VERSION 5.7 ;
  NAMESCASESENSITIVE ON ;
  NOWIREEXTENSIONATPIN ON ;
  DIVIDERCHAR "/" ;
  BUSBITCHARS "[]" ;
UNITS
  DATABASE MICRONS 200 ;
END UNITS

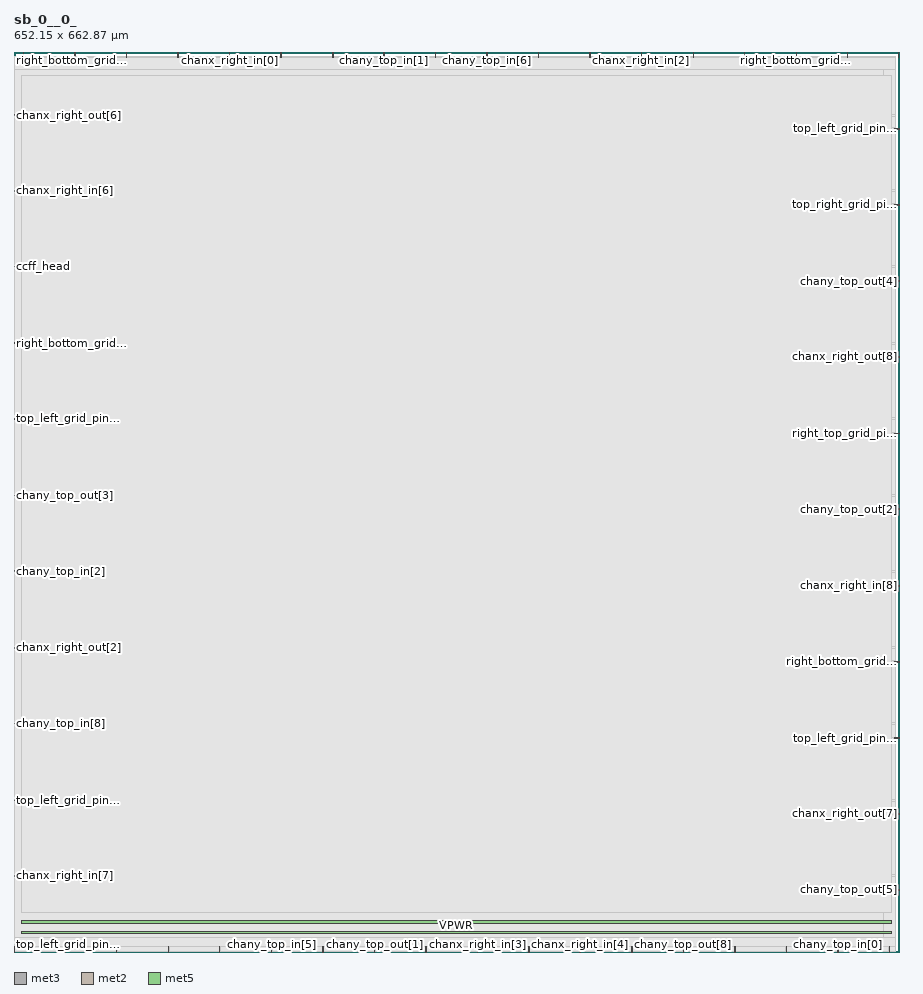
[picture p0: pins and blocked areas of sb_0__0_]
MACRO sb_0__0_
  CLASS BLOCK ;
  FOREIGN sb_0__0_ ;
  ORIGIN 0.000 0.000 ;
  SIZE 652.150 BY 662.870 ;
  PIN ccff_head
    DIRECTION INPUT ;
    PORT
      LAYER met3 ;
        RECT 0.000 504.600 4.000 505.200 ;
    END
  END ccff_head
  PIN ccff_tail
    DIRECTION OUTPUT TRISTATE ;
    PORT
      LAYER met2 ;
        RECT 234.690 658.870 234.970 662.870 ;
    END
  END ccff_tail
  PIN chanx_right_in[0]
    DIRECTION INPUT ;
    PORT
      LAYER met2 ;
        RECT 158.790 658.870 159.070 662.870 ;
    END
  END chanx_right_in[0]
  PIN chanx_right_in[1]
    DIRECTION INPUT ;
    PORT
      LAYER met2 ;
        RECT 44.710 658.870 44.990 662.870 ;
    END
  END chanx_right_in[1]
  PIN chanx_right_in[2]
    DIRECTION INPUT ;
    PORT
      LAYER met2 ;
        RECT 461.930 658.870 462.210 662.870 ;
    END
  END chanx_right_in[2]
  PIN chanx_right_in[3]
    DIRECTION INPUT ;
    PORT
      LAYER met2 ;
        RECT 341.410 0.000 341.690 4.000 ;
    END
  END chanx_right_in[3]
  PIN chanx_right_in[4]
    DIRECTION INPUT ;
    PORT
      LAYER met2 ;
        RECT 416.850 0.000 417.130 4.000 ;
    END
  END chanx_right_in[4]
  PIN chanx_right_in[5]
    DIRECTION INPUT ;
    PORT
      LAYER met2 ;
        RECT 386.030 658.870 386.310 662.870 ;
    END
  END chanx_right_in[5]
  PIN chanx_right_in[6]
    DIRECTION INPUT ;
    PORT
      LAYER met3 ;
        RECT 0.000 560.360 4.000 560.960 ;
    END
  END chanx_right_in[6]
  PIN chanx_right_in[7]
    DIRECTION INPUT ;
    PORT
      LAYER met3 ;
        RECT 0.000 55.800 4.000 56.400 ;
    END
  END chanx_right_in[7]
  PIN chanx_right_in[8]
    DIRECTION INPUT ;
    PORT
      LAYER met3 ;
        RECT 648.150 269.320 652.150 269.920 ;
    END
  END chanx_right_in[8]
  PIN chanx_right_out[0]
    DIRECTION OUTPUT TRISTATE ;
    PORT
      LAYER met2 ;
        RECT 120.610 658.870 120.890 662.870 ;
    END
  END chanx_right_out[0]
  PIN chanx_right_out[1]
    DIRECTION OUTPUT TRISTATE ;
    PORT
      LAYER met2 ;
        RECT 455.030 0.000 455.310 4.000 ;
    END
  END chanx_right_out[1]
  PIN chanx_right_out[2]
    DIRECTION OUTPUT TRISTATE ;
    PORT
      LAYER met3 ;
        RECT 0.000 223.760 4.000 224.360 ;
    END
  END chanx_right_out[2]
  PIN chanx_right_out[3]
    DIRECTION OUTPUT TRISTATE ;
    PORT
      LAYER met2 ;
        RECT 500.110 658.870 500.390 662.870 ;
    END
  END chanx_right_out[3]
  PIN chanx_right_out[4]
    DIRECTION OUTPUT TRISTATE ;
    PORT
      LAYER met2 ;
        RECT 75.530 0.000 75.810 4.000 ;
    END
  END chanx_right_out[4]
  PIN chanx_right_out[5]
    DIRECTION OUTPUT TRISTATE ;
    PORT
      LAYER met2 ;
        RECT 644.550 0.000 644.830 4.000 ;
    END
  END chanx_right_out[5]
  PIN chanx_right_out[6]
    DIRECTION OUTPUT TRISTATE ;
    PORT
      LAYER met3 ;
        RECT 0.000 616.120 4.000 616.720 ;
    END
  END chanx_right_out[6]
  PIN chanx_right_out[7]
    DIRECTION OUTPUT TRISTATE ;
    PORT
      LAYER met3 ;
        RECT 648.150 101.360 652.150 101.960 ;
    END
  END chanx_right_out[7]
  PIN chanx_right_out[8]
    DIRECTION OUTPUT TRISTATE ;
    PORT
      LAYER met3 ;
        RECT 648.150 437.960 652.150 438.560 ;
    END
  END chanx_right_out[8]
  PIN chany_top_in[0]
    DIRECTION INPUT ;
    PORT
      LAYER met2 ;
        RECT 606.830 0.000 607.110 4.000 ;
    END
  END chany_top_in[0]
  PIN chany_top_in[1]
    DIRECTION INPUT ;
    PORT
      LAYER met2 ;
        RECT 272.410 658.870 272.690 662.870 ;
    END
  END chany_top_in[1]
  PIN chany_top_in[2]
    DIRECTION INPUT ;
    PORT
      LAYER met3 ;
        RECT 0.000 280.200 4.000 280.800 ;
    END
  END chany_top_in[2]
  PIN chany_top_in[3]
    DIRECTION INPUT ;
    PORT
      LAYER met2 ;
        RECT 568.650 0.000 568.930 4.000 ;
    END
  END chany_top_in[3]
  PIN chany_top_in[4]
    DIRECTION INPUT ;
    PORT
      LAYER met2 ;
        RECT 424.210 658.870 424.490 662.870 ;
    END
  END chany_top_in[4]
  PIN chany_top_in[5]
    DIRECTION INPUT ;
    PORT
      LAYER met2 ;
        RECT 189.610 0.000 189.890 4.000 ;
    END
  END chany_top_in[5]
  PIN chany_top_in[6]
    DIRECTION INPUT ;
    PORT
      LAYER met2 ;
        RECT 348.310 658.870 348.590 662.870 ;
    END
  END chany_top_in[6]
  PIN chany_top_in[7]
    DIRECTION INPUT ;
    PORT
      LAYER met2 ;
        RECT 530.930 0.000 531.210 4.000 ;
    END
  END chany_top_in[7]
  PIN chany_top_in[8]
    DIRECTION INPUT ;
    PORT
      LAYER met3 ;
        RECT 0.000 168.000 4.000 168.600 ;
    END
  END chany_top_in[8]
  PIN chany_top_out[0]
    DIRECTION OUTPUT TRISTATE ;
    PORT
      LAYER met2 ;
        RECT 82.890 658.870 83.170 662.870 ;
    END
  END chany_top_out[0]
  PIN chany_top_out[1]
    DIRECTION OUTPUT TRISTATE ;
    PORT
      LAYER met2 ;
        RECT 265.510 0.000 265.790 4.000 ;
    END
  END chany_top_out[1]
  PIN chany_top_out[2]
    DIRECTION OUTPUT TRISTATE ;
    PORT
      LAYER met3 ;
        RECT 648.150 325.760 652.150 326.360 ;
    END
  END chany_top_out[2]
  PIN chany_top_out[3]
    DIRECTION OUTPUT TRISTATE ;
    PORT
      LAYER met3 ;
        RECT 0.000 335.960 4.000 336.560 ;
    END
  END chany_top_out[3]
  PIN chany_top_out[4]
    DIRECTION OUTPUT TRISTATE ;
    PORT
      LAYER met3 ;
        RECT 648.150 493.720 652.150 494.320 ;
    END
  END chany_top_out[4]
  PIN chany_top_out[5]
    DIRECTION OUTPUT TRISTATE ;
    PORT
      LAYER met3 ;
        RECT 648.150 45.600 652.150 46.200 ;
    END
  END chany_top_out[5]
  PIN chany_top_out[6]
    DIRECTION OUTPUT TRISTATE ;
    PORT
      LAYER met2 ;
        RECT 151.430 0.000 151.710 4.000 ;
    END
  END chany_top_out[6]
  PIN chany_top_out[7]
    DIRECTION OUTPUT TRISTATE ;
    PORT
      LAYER met2 ;
        RECT 113.710 0.000 113.990 4.000 ;
    END
  END chany_top_out[7]
  PIN chany_top_out[8]
    DIRECTION OUTPUT TRISTATE ;
    PORT
      LAYER met2 ;
        RECT 492.750 0.000 493.030 4.000 ;
    END
  END chany_top_out[8]
  PIN pReset
    DIRECTION INPUT ;
    PORT
      LAYER met2 ;
        RECT 379.130 0.000 379.410 4.000 ;
    END
  END pReset
  PIN prog_clk
    DIRECTION INPUT ;
    PORT
      LAYER met2 ;
        RECT 303.230 0.000 303.510 4.000 ;
    END
  END prog_clk
  PIN right_bottom_grid_pin_11_
    DIRECTION INPUT ;
    PORT
      LAYER met2 ;
        RECT 227.330 0.000 227.610 4.000 ;
    END
  END right_bottom_grid_pin_11_
  PIN right_bottom_grid_pin_13_
    DIRECTION INPUT ;
    PORT
      LAYER met2 ;
        RECT 6.990 658.870 7.270 662.870 ;
    END
  END right_bottom_grid_pin_13_
  PIN right_bottom_grid_pin_15_
    DIRECTION INPUT ;
    PORT
      LAYER met2 ;
        RECT 37.810 0.000 38.090 4.000 ;
    END
  END right_bottom_grid_pin_15_
  PIN right_bottom_grid_pin_1_
    DIRECTION INPUT ;
    PORT
      LAYER met2 ;
        RECT 537.830 658.870 538.110 662.870 ;
    END
  END right_bottom_grid_pin_1_
  PIN right_bottom_grid_pin_3_
    DIRECTION INPUT ;
    PORT
      LAYER met3 ;
        RECT 648.150 213.560 652.150 214.160 ;
    END
  END right_bottom_grid_pin_3_
  PIN right_bottom_grid_pin_5_
    DIRECTION INPUT ;
    PORT
      LAYER met3 ;
        RECT 0.000 448.160 4.000 448.760 ;
    END
  END right_bottom_grid_pin_5_
  PIN right_bottom_grid_pin_7_
    DIRECTION INPUT ;
    PORT
      LAYER met2 ;
        RECT 310.130 658.870 310.410 662.870 ;
    END
  END right_bottom_grid_pin_7_
  PIN right_bottom_grid_pin_9_
    DIRECTION INPUT ;
    PORT
      LAYER met2 ;
        RECT 576.010 658.870 576.290 662.870 ;
    END
  END right_bottom_grid_pin_9_
  PIN right_top_grid_pin_10_
    DIRECTION INPUT ;
    PORT
      LAYER met3 ;
        RECT 648.150 381.520 652.150 382.120 ;
    END
  END right_top_grid_pin_10_
  PIN top_left_grid_pin_11_
    DIRECTION INPUT ;
    PORT
      LAYER met3 ;
        RECT 648.150 157.120 652.150 157.720 ;
    END
  END top_left_grid_pin_11_
  PIN top_left_grid_pin_13_
    DIRECTION INPUT ;
    PORT
      LAYER met3 ;
        RECT 0.000 111.560 4.000 112.160 ;
    END
  END top_left_grid_pin_13_
  PIN top_left_grid_pin_15_
    DIRECTION INPUT ;
    PORT
      LAYER met2 ;
        RECT 613.730 658.870 614.010 662.870 ;
    END
  END top_left_grid_pin_15_
  PIN top_left_grid_pin_1_
    DIRECTION INPUT ;
    PORT
      LAYER met2 ;
        RECT 651.450 658.870 651.730 662.870 ;
    END
  END top_left_grid_pin_1_
  PIN top_left_grid_pin_3_
    DIRECTION INPUT ;
    PORT
      LAYER met3 ;
        RECT 0.000 392.400 4.000 393.000 ;
    END
  END top_left_grid_pin_3_
  PIN top_left_grid_pin_5_
    DIRECTION INPUT ;
    PORT
      LAYER met2 ;
        RECT 196.510 658.870 196.790 662.870 ;
    END
  END top_left_grid_pin_5_
  PIN top_left_grid_pin_7_
    DIRECTION INPUT ;
    PORT
      LAYER met3 ;
        RECT 648.150 605.920 652.150 606.520 ;
    END
  END top_left_grid_pin_7_
  PIN top_left_grid_pin_9_
    DIRECTION INPUT ;
    PORT
      LAYER met2 ;
        RECT 0.090 0.000 0.370 4.000 ;
    END
  END top_left_grid_pin_9_
  PIN top_right_grid_pin_11_
    DIRECTION INPUT ;
    PORT
      LAYER met3 ;
        RECT 648.150 550.160 652.150 550.760 ;
    END
  END top_right_grid_pin_11_
  PIN VPWR
    DIRECTION INPUT ;
    USE POWER ;
    PORT
      LAYER met5 ;
        RECT 5.520 13.840 646.300 15.440 ;
    END
  END VPWR
  PIN VGND
    DIRECTION INPUT ;
    USE GROUND ;
    PORT
      LAYER met5 ;
        RECT 5.520 21.340 646.300 22.940 ;
    END
  END VGND
  OBS
      LAYER li1 ;
        RECT 5.520 10.795 646.300 650.165 ;
      LAYER met1 ;
        RECT 0.530 0.380 648.990 659.220 ;
      LAYER met2 ;
        RECT 0.090 658.590 6.710 659.330 ;
        RECT 7.550 658.590 44.430 659.330 ;
        RECT 45.270 658.590 82.610 659.330 ;
        RECT 83.450 658.590 120.330 659.330 ;
        RECT 121.170 658.590 158.510 659.330 ;
        RECT 159.350 658.590 196.230 659.330 ;
        RECT 197.070 658.590 234.410 659.330 ;
        RECT 235.250 658.590 272.130 659.330 ;
        RECT 272.970 658.590 309.850 659.330 ;
        RECT 310.690 658.590 348.030 659.330 ;
        RECT 348.870 658.590 385.750 659.330 ;
        RECT 386.590 658.590 423.930 659.330 ;
        RECT 424.770 658.590 461.650 659.330 ;
        RECT 462.490 658.590 499.830 659.330 ;
        RECT 500.670 658.590 537.550 659.330 ;
        RECT 538.390 658.590 575.730 659.330 ;
        RECT 576.570 658.590 613.450 659.330 ;
        RECT 614.290 658.590 648.970 659.330 ;
        RECT 0.090 4.280 648.970 658.590 ;
        RECT 0.650 0.270 37.530 4.280 ;
        RECT 38.370 0.270 75.250 4.280 ;
        RECT 76.090 0.270 113.430 4.280 ;
        RECT 114.270 0.270 151.150 4.280 ;
        RECT 151.990 0.270 189.330 4.280 ;
        RECT 190.170 0.270 227.050 4.280 ;
        RECT 227.890 0.270 265.230 4.280 ;
        RECT 266.070 0.270 302.950 4.280 ;
        RECT 303.790 0.270 341.130 4.280 ;
        RECT 341.970 0.270 378.850 4.280 ;
        RECT 379.690 0.270 416.570 4.280 ;
        RECT 417.410 0.270 454.750 4.280 ;
        RECT 455.590 0.270 492.470 4.280 ;
        RECT 493.310 0.270 530.650 4.280 ;
        RECT 531.490 0.270 568.370 4.280 ;
        RECT 569.210 0.270 606.550 4.280 ;
        RECT 607.390 0.270 644.270 4.280 ;
        RECT 645.110 0.270 648.970 4.280 ;
      LAYER met3 ;
        RECT 0.270 617.120 649.210 650.245 ;
        RECT 4.400 615.720 649.210 617.120 ;
        RECT 0.270 606.920 649.210 615.720 ;
        RECT 0.270 605.520 647.750 606.920 ;
        RECT 0.270 561.360 649.210 605.520 ;
        RECT 4.400 559.960 649.210 561.360 ;
        RECT 0.270 551.160 649.210 559.960 ;
        RECT 0.270 549.760 647.750 551.160 ;
        RECT 0.270 505.600 649.210 549.760 ;
        RECT 4.400 504.200 649.210 505.600 ;
        RECT 0.270 494.720 649.210 504.200 ;
        RECT 0.270 493.320 647.750 494.720 ;
        RECT 0.270 449.160 649.210 493.320 ;
        RECT 4.400 447.760 649.210 449.160 ;
        RECT 0.270 438.960 649.210 447.760 ;
        RECT 0.270 437.560 647.750 438.960 ;
        RECT 0.270 393.400 649.210 437.560 ;
        RECT 4.400 392.000 649.210 393.400 ;
        RECT 0.270 382.520 649.210 392.000 ;
        RECT 0.270 381.120 647.750 382.520 ;
        RECT 0.270 336.960 649.210 381.120 ;
        RECT 4.400 335.560 649.210 336.960 ;
        RECT 0.270 326.760 649.210 335.560 ;
        RECT 0.270 325.360 647.750 326.760 ;
        RECT 0.270 281.200 649.210 325.360 ;
        RECT 4.400 279.800 649.210 281.200 ;
        RECT 0.270 270.320 649.210 279.800 ;
        RECT 0.270 268.920 647.750 270.320 ;
        RECT 0.270 224.760 649.210 268.920 ;
        RECT 4.400 223.360 649.210 224.760 ;
        RECT 0.270 214.560 649.210 223.360 ;
        RECT 0.270 213.160 647.750 214.560 ;
        RECT 0.270 169.000 649.210 213.160 ;
        RECT 4.400 167.600 649.210 169.000 ;
        RECT 0.270 158.120 649.210 167.600 ;
        RECT 0.270 156.720 647.750 158.120 ;
        RECT 0.270 112.560 649.210 156.720 ;
        RECT 4.400 111.160 649.210 112.560 ;
        RECT 0.270 102.360 649.210 111.160 ;
        RECT 0.270 100.960 647.750 102.360 ;
        RECT 0.270 56.800 649.210 100.960 ;
        RECT 4.400 55.400 649.210 56.800 ;
        RECT 0.270 46.600 649.210 55.400 ;
        RECT 0.270 45.200 647.750 46.600 ;
        RECT 0.270 10.715 649.210 45.200 ;
      LAYER met4 ;
        RECT 0.295 10.640 640.320 650.320 ;
      LAYER met5 ;
        RECT 5.520 28.840 646.300 645.440 ;
  END
END sb_0__0_
END LIBRARY

